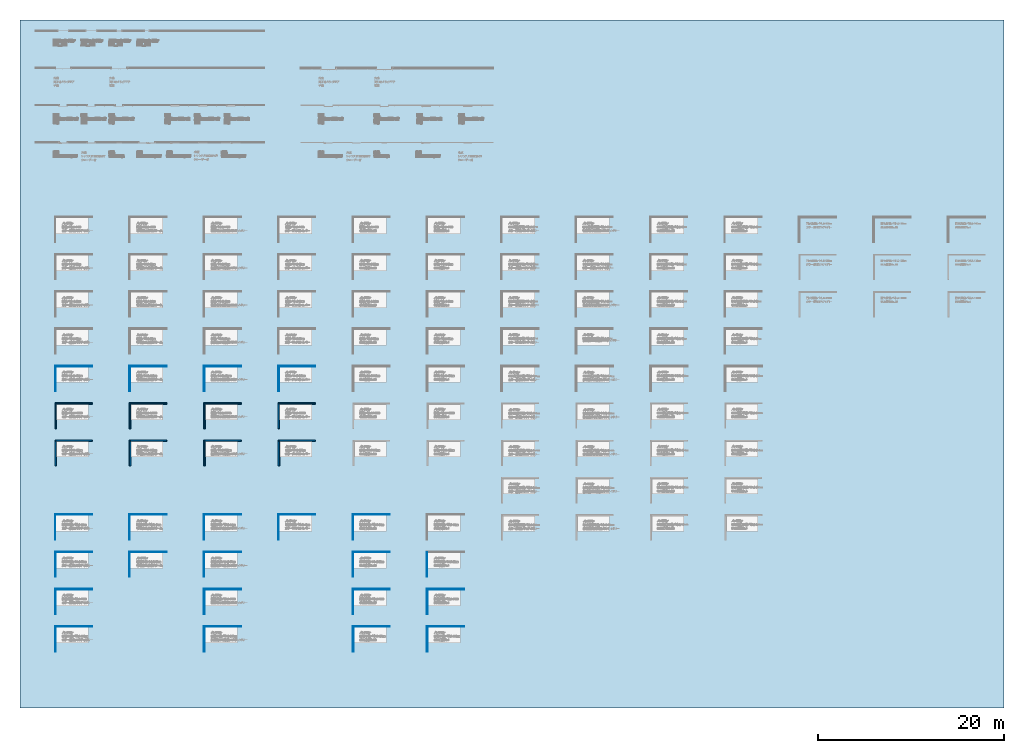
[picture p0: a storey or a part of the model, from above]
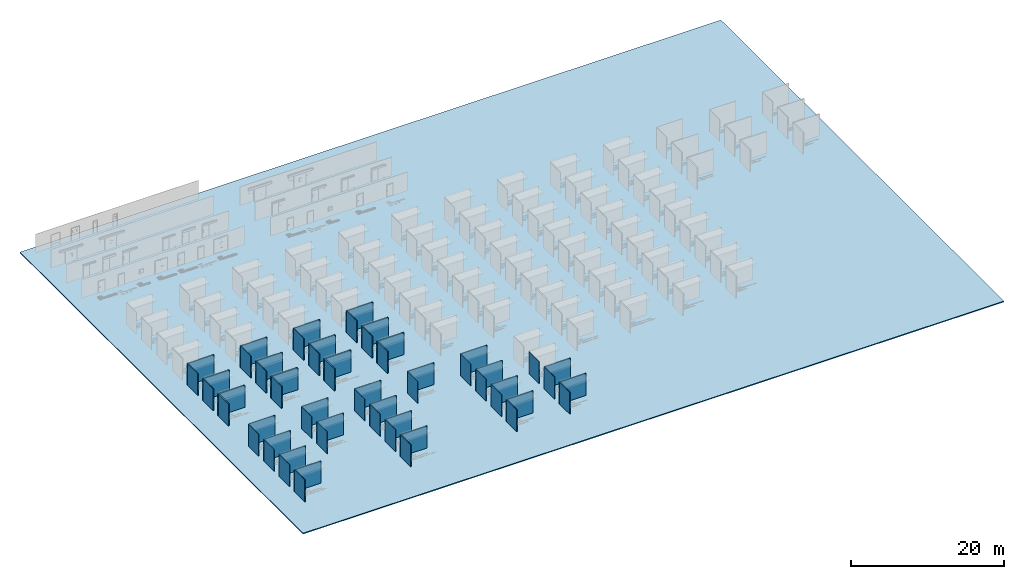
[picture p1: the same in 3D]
Properties of the parts of a building model (IFC2X3)

# File
Description: ViewDefinition [CoordinationView_V2.0], RevitIdentifiers [VersionGUID: c6d43900-80c5-4006-b426-6beda343c6e3, NumberOfSaves: 112], CoordinateReference [CoordinateBase: 共有座標]
File name: プロジェクト番号
Time: 2023-09-21T10:30:06
Written by: ODA IFC SDK 22.8
Made in: 22.1.40.58 - Exporter 22.6.2.0 - 代替 UI 22.6.2.0

# IfcProject, プロジェクト番号
LongName: プロジェクト名; Phase: プロジェクト ステータス

# IfcSite, Default
RefLatitude: 35, 41, 6, 4943; RefLongitude: 139, 45, 3, 625488; RefElevation: 0 mm

# IfcBuilding
Pset_BuildingCommon - NumberOfStoreys: 1

# IfcBuildingStorey: レベル:レベル記号 (2)
Name | LongName | Elevation (mm)
レベル 1 | レベル 1 | 500
レベル 2 | レベル 2 | 3500

# IfcBuildingStorey: レベル:レベル記号 - 基準, 設計GL
LongName: 設計GL; Elevation: 0 mm

# IfcBuildingElementProxy: 立体文字:200㎜ MS Pゴシック (136)
In: レベル 1
Pset_BuildingElementProxyCommon - Reference: 200㎜ MS Pゴシック; sets with these values: 2
Pset_ProvisionForVoid - Shape: Undefined
Name (立体文字:200㎜ MS Pゴシック:...) | Width (mm) | Height (mm) = Depth (mm)
365015 | 239.087 | 18.3913
365466 | 256.329 | 25.2881
365474 | 239.087 | 18.3913
365482 | 239.087 | 18.3913
365548 | 25.2881 | 158.625
365597 | 25.2881 | 158.625
365607 | 12.644 | 293.112
365695 | 66.6686 | 13.7935
365733 | 12.644 | 293.112
365739 | 12.644 | 293.112
365747 | 12.644 | 293.112
365796 | 25.2881 | 158.625
365804 | 66.6686 | 13.7935
365825 | 239.087 | 18.3913
365826 | 256.329 | 25.2881
365827 | 239.087 | 18.3913
365829 | 25.2881 | 158.625
365830 | 25.2881 | 158.625
365831 | 66.6686 | 13.7935
365833 | 66.6686 | 13.7935
365937 | 256.329 | 25.2881
365998 | 256.329 | 25.2881
366008 | 256.329 | 25.2881
366018 | 256.329 | 25.2881
366026 | 256.329 | 25.2881
366036 | 256.329 | 25.2881
366044 | 256.329 | 25.2881
366052 | 256.329 | 25.2881
366131 | 256.329 | 25.2881
366139 | 256.329 | 25.2881
366147 | 256.329 | 25.2881
366174 | 66.6686 | 13.7935
366219 | 66.6686 | 13.7935
366229 | 66.6686 | 13.7935
366237 | 66.6686 | 13.7935
366245 | 66.6686 | 13.7935
366253 | 66.6686 | 13.7935
366261 | 256.329 | 25.2881
366271 | 66.6686 | 13.7935
366324 | 66.6686 | 13.7935
366393 | 256.329 | 25.2881
366402 | 256.329 | 25.2881
366411
366422
366503 | 256.329 | 25.2881
366504 | 256.329 | 25.2881
366505
366506
366538 | 256.329 | 25.2881
366539 | 256.329 | 25.2881
366540
366541
366549 | 256.329 | 25.2881
366550 | 256.329 | 25.2881
366551
366552
366560 | 256.329 | 25.2881
366561 | 256.329 | 25.2881
366562
366563
366571 | 256.329 | 25.2881
366572 | 256.329 | 25.2881
366573
366574
366582 | 256.329 | 25.2881
366583 | 256.329 | 25.2881
366584
366585
366593 | 256.329 | 25.2881
366594 | 256.329 | 25.2881
366595
366596
366640 | 256.329 | 25.2881
366642
366643
366651 | 256.329 | 25.2881
366653
366654
366664 | 256.329 | 25.2881
366666
366667
453311 | 256.329 | 25.2881
453312 | 256.329 | 25.2881
453313 | 256.329 | 25.2881
453314 | 256.329 | 25.2881
453370 | 256.329 | 25.2881
453371 | 256.329 | 25.2881
453372 | 256.329 | 25.2881
453373 | 256.329 | 25.2881
453418 | 256.329 | 25.2881
453479 | 163.223 | 21.8397
457776 | 239.087 | 18.3913
461452 | 256.329 | 25.2881
465981 | 239.087 | 18.3913
470227 | 239.087 | 18.3913
473891 | 256.329 | 25.2881
520192 | 25.2881 | 158.625
524008 | 25.2881 | 158.625
535722 | 66.6686 | 13.7935
551148 | 25.2881 | 158.625
555094 | 66.6686 | 13.7935
720312 | 256.329 | 25.2881
720313 | 256.329 | 25.2881
720314 | 256.329 | 25.2881
720315 | 256.329 | 25.2881
720352 | 256.329 | 25.2881
720353 | 256.329 | 25.2881
720354 | 256.329 | 25.2881
720355 | 256.329 | 25.2881
720365 | 256.329 | 25.2881
720410 | 25.2881 | 26.4375
720506 | 25.2881 | 26.4375
720608 | 163.223 | 21.8397
720616 | 163.223 | 21.8397
720701 | 25.2881 | 26.4375
721289 | 25.2881 | 26.4375
721290 | 25.2881 | 26.4375
721298 | 25.2881 | 26.4375
721299 | 25.2881 | 26.4375
721307 | 25.2881 | 26.4375
721308 | 25.2881 | 26.4375
721316 | 25.2881 | 26.4375
721317 | 25.2881 | 26.4375
721327 | 25.2881 | 26.4375
721328 | 25.2881 | 26.4375
721336 | 25.2881 | 26.4375
721337 | 25.2881 | 26.4375
721345 | 25.2881 | 26.4375
721346 | 25.2881 | 26.4375
721354 | 25.2881 | 26.4375
721355 | 25.2881 | 26.4375
721387 | 25.2881 | 26.4375
722106 | 25.2881 | 26.4375
722107 | 25.2881 | 26.4375
722115 | 25.2881 | 26.4375
722116 | 25.2881 | 26.4375

# IfcCovering: 天井:g-p_ECO不燃断熱パネルt102+天井下地材t125_900x2700 (4)
In: レベル 1
Type - PredefinedType: CEILING
Type - Pset_CoveringCommon - TotalThickness: 227 mm
Material: <Unnamed> 125 mm, g-p_フェノールフォーム 102 mm
Pset_CoveringCommon - Reference: g-p_ECO不燃断熱パネルt102+天井下地材t125_900x2700; Finish: g-p_フェノールフォーム;
Pset_QuantityTakeOff - Reference: g-p_ECO不燃断熱パネルt102+天井下地材t125_900x2700
Name (天井:g-p_ECO不燃断熱パネルt102+天井下地材t125_900x2700:...)
453344
720326
720424
720520

# IfcCovering: 天井:g-p_ECO不燃断熱パネルt118+天井下地材t125_900x2700 (4)
In: レベル 1
Type - PredefinedType: CEILING
Type - Pset_CoveringCommon - TotalThickness: 243 mm
Material: <Unnamed> 125 mm, g-p_フェノールフォーム 118 mm
Pset_CoveringCommon - Reference: g-p_ECO不燃断熱パネルt118+天井下地材t125_900x2700; Finish: g-p_フェノールフォーム;
Pset_QuantityTakeOff - Reference: g-p_ECO不燃断熱パネルt118+天井下地材t125_900x2700
Name (天井:g-p_ECO不燃断熱パネルt118+天井下地材t125_900x2700:...)
453351
720333
720431
720527

# IfcCovering: 天井:g-p_ECO不燃断熱パネルt134+天井下地材t125_900x2700 (4)
In: レベル 1
Type - PredefinedType: CEILING
Type - Pset_CoveringCommon - TotalThickness: 259 mm
Material: <Unnamed> 125 mm, g-p_フェノールフォーム 134 mm
Pset_CoveringCommon - Reference: g-p_ECO不燃断熱パネルt134+天井下地材t125_900x2700; Finish: g-p_フェノールフォーム;
Pset_QuantityTakeOff - Reference: g-p_ECO不燃断熱パネルt134+天井下地材t125_900x2700
Name (天井:g-p_ECO不燃断熱パネルt134+天井下地材t125_900x2700:...)
453358
720340
720438
720534

# IfcCovering: 天井:g-p_ECO不燃断熱パネルt152+天井下地材t125_900x2700 (4)
In: レベル 1
Type - PredefinedType: CEILING
Type - Pset_CoveringCommon - TotalThickness: 277 mm
Material: <Unnamed> 125 mm, g-p_フェノールフォーム 152 mm
Pset_CoveringCommon - Reference: g-p_ECO不燃断熱パネルt152+天井下地材t125_900x2700; Finish: g-p_フェノールフォーム;
Pset_QuantityTakeOff - Reference: g-p_ECO不燃断熱パネルt152+天井下地材t125_900x2700
Name (天井:g-p_ECO不燃断熱パネルt152+天井下地材t125_900x2700:...)
453365
720347
720445
720541

# IfcCovering: 天井:g-p_ECO不燃断熱パネルt168+天井下地材t125_900x2700 (4)
In: レベル 1
Type - PredefinedType: CEILING
Type - Pset_CoveringCommon - TotalThickness: 293 mm
Material: <Unnamed> 125 mm, g-p_フェノールフォーム 168 mm
Pset_CoveringCommon - Reference: g-p_ECO不燃断熱パネルt168+天井下地材t125_900x2700; Finish: g-p_フェノールフォーム;
Pset_QuantityTakeOff - Reference: g-p_ECO不燃断熱パネルt168+天井下地材t125_900x2700
Name (天井:g-p_ECO不燃断熱パネルt168+天井下地材t125_900x2700:...)
453413
720360
720458
720554

# IfcCovering: 天井:g-p_ECO不燃断熱パネルt52+天井下地材t125_900x2700 (8)
In: レベル 1
Type - PredefinedType: CEILING
Type - Pset_CoveringCommon - TotalThickness: 177 mm
Material: <Unnamed> 125 mm, g-p_フェノールフォーム 52 mm
Pset_CoveringCommon - Reference: g-p_ECO不燃断熱パネルt52+天井下地材t125_900x2700; Finish: g-p_フェノールフォーム;
Pset_QuantityTakeOff - Reference: g-p_ECO不燃断熱パネルt52+天井下地材t125_900x2700
Name (天井:g-p_ECO不燃断熱パネルt52+天井下地材t125_900x2700:...)
453292
719525
720293
720368
720391
720466
720487
720562

# IfcCovering: 天井:g-p_ECO不燃断熱パネルt68+天井下地材t125_900x2700 (4)
In: レベル 1
Type - PredefinedType: CEILING
Type - Pset_CoveringCommon - TotalThickness: 193 mm
Material: <Unnamed> 125 mm, g-p_フェノールフォーム 68 mm
Pset_CoveringCommon - Reference: g-p_ECO不燃断熱パネルt68+天井下地材t125_900x2700; Finish: g-p_フェノールフォーム;
Pset_QuantityTakeOff - Reference: g-p_ECO不燃断熱パネルt68+天井下地材t125_900x2700
Name (天井:g-p_ECO不燃断熱パネルt68+天井下地材t125_900x2700:...)
453299
720300
720398
720494

# IfcCovering: 天井:g-p_ECO不燃断熱パネルt87+天井下地材t125_900x2700 (4)
In: レベル 1
Type - PredefinedType: CEILING
Type - Pset_CoveringCommon - TotalThickness: 212 mm
Material: <Unnamed> 125 mm, g-p_フェノールフォーム 87 mm
Pset_CoveringCommon - Reference: g-p_ECO不燃断熱パネルt87+天井下地材t125_900x2700; Finish: g-p_フェノールフォーム;
Pset_QuantityTakeOff - Reference: g-p_ECO不燃断熱パネルt87+天井下地材t125_900x2700
Name (天井:g-p_ECO不燃断熱パネルt87+天井下地材t125_900x2700:...)
453306
720307
720405
720501

# IfcCovering: 天井:g-p_不燃断熱パネルt100+天井下地材t125_900x2700 (4)
In: レベル 1
Type - PredefinedType: CEILING
Type - Pset_CoveringCommon - TotalThickness: 225 mm
Material: <Unnamed> 125 mm, g-p_硬質イソシアヌレートフォーム 100 mm
Pset_CoveringCommon - Reference: g-p_不燃断熱パネルt100+天井下地材t125_900x2700; Finish: g-p_硬質イソシアヌレートフォーム;
Pset_QuantityTakeOff - Reference: g-p_不燃断熱パネルt100+天井下地材t125_900x2700
Name (天井:g-p_不燃断熱パネルt100+天井下地材t125_900x2700:...)
356772
357047
357259
357363

# IfcCovering: 天井:g-p_不燃断熱パネルt44+天井下地材t125_900x2700 (6)
In: レベル 1
Type - PredefinedType: CEILING
Type - Pset_CoveringCommon - TotalThickness: 169 mm
Material: <Unnamed> 125 mm, g-p_硬質イソシアヌレートフォーム 44 mm
Pset_CoveringCommon - Reference: g-p_不燃断熱パネルt44+天井下地材t125_900x2700; Finish: g-p_硬質イソシアヌレートフォーム;
Pset_QuantityTakeOff - Reference: g-p_不燃断熱パネルt44+天井下地材t125_900x2700
Name (天井:g-p_不燃断熱パネルt44+天井下地材t125_900x2700:...)
356722
356920
357026
357132
357238
357342

# IfcCovering: 天井:g-p_不燃断熱パネルt50+天井下地材t125_900x2700 (5)
In: レベル 1
Type - PredefinedType: CEILING
Type - Pset_CoveringCommon - TotalThickness: 175 mm
Material: <Unnamed> 125 mm, g-p_硬質イソシアヌレートフォーム 50 mm
Pset_CoveringCommon - Reference: g-p_不燃断熱パネルt50+天井下地材t125_900x2700; Finish: g-p_硬質イソシアヌレートフォーム;
Pset_QuantityTakeOff - Reference: g-p_不燃断熱パネルt50+天井下地材t125_900x2700
Name (天井:g-p_不燃断熱パネルt50+天井下地材t125_900x2700:...)
356740
356927
357033
357245
357349

# IfcCovering: 天井:g-p_不燃断熱パネルt77+天井下地材t125_900x2700 (4)
In: レベル 1
Type - PredefinedType: CEILING
Type - Pset_CoveringCommon - TotalThickness: 202 mm
Material: <Unnamed> 125 mm, g-p_硬質イソシアヌレートフォーム 77 mm
Pset_CoveringCommon - Reference: g-p_不燃断熱パネルt77+天井下地材t125_900x2700; Finish: g-p_硬質イソシアヌレートフォーム;
Pset_QuantityTakeOff - Reference: g-p_不燃断熱パネルt77+天井下地材t125_900x2700
Name (天井:g-p_不燃断熱パネルt77+天井下地材t125_900x2700:...)
356756
357040
357252
357356

# IfcCovering: 天井:g-p_断熱パネルt100+天井下地材t125_900x2700 (6)
In: レベル 1
Type - PredefinedType: CEILING
Type - Pset_CoveringCommon - TotalThickness: 225 mm
Material: <Unnamed> 125 mm, g-p_硬質ウレタンフォーム 100 mm
Pset_CoveringCommon - Reference: g-p_断熱パネルt100+天井下地材t125_900x2700; Finish: g-p_硬質ウレタンフォーム;
Pset_QuantityTakeOff - Reference: g-p_断熱パネルt100+天井下地材t125_900x2700
Name (天井:g-p_断熱パネルt100+天井下地材t125_900x2700:...)
356674
356899
357005
357111
357217
357321

# IfcCovering: 天井:g-p_断熱パネルt127+天井下地材t125_900x2700 (6)
In: レベル 1
Type - PredefinedType: CEILING
Type - Pset_CoveringCommon - TotalThickness: 252 mm
Material: <Unnamed> 125 mm, g-p_硬質ウレタンフォーム 127 mm
Pset_CoveringCommon - Reference: g-p_断熱パネルt127+天井下地材t125_900x2700; Finish: g-p_硬質ウレタンフォーム;
Pset_QuantityTakeOff - Reference: g-p_断熱パネルt127+天井下地材t125_900x2700
Name (天井:g-p_断熱パネルt127+天井下地材t125_900x2700:...)
356690
356906
357012
357118
357224
357328

# IfcCovering: 天井:g-p_断熱パネルt152+天井下地材t125_900x2700 (6)
In: レベル 1
Type - PredefinedType: CEILING
Type - Pset_CoveringCommon - TotalThickness: 277 mm
Material: <Unnamed> 125 mm, g-p_硬質ウレタンフォーム 152 mm
Pset_CoveringCommon - Reference: g-p_断熱パネルt152+天井下地材t125_900x2700; Finish: g-p_硬質ウレタンフォーム;
Pset_QuantityTakeOff - Reference: g-p_断熱パネルt152+天井下地材t125_900x2700
Name (天井:g-p_断熱パネルt152+天井下地材t125_900x2700:...)
356706
356913
357019
357125
357231
357335

# IfcCovering: 天井:g-p_断熱パネルt44+天井下地材t125_900x2700 (6)
In: レベル 1
Type - PredefinedType: CEILING
Type - Pset_CoveringCommon - TotalThickness: 169 mm
Material: <Unnamed> 125 mm, g-p_硬質ウレタンフォーム 44 mm
Pset_CoveringCommon - Reference: g-p_断熱パネルt44+天井下地材t125_900x2700; Finish: g-p_硬質ウレタンフォーム;
Pset_QuantityTakeOff - Reference: g-p_断熱パネルt44+天井下地材t125_900x2700
Name (天井:g-p_断熱パネルt44+天井下地材t125_900x2700:...)
282149
356849
356955
357061
357167
357271

# IfcCovering: 天井:g-p_断熱パネルt50+天井下地材t125_900x2700 (6)
In: レベル 1
Type - PredefinedType: CEILING
Type - Pset_CoveringCommon - TotalThickness: 175 mm
Material: <Unnamed> 125 mm, g-p_硬質ウレタンフォーム 50 mm
Pset_CoveringCommon - Reference: g-p_断熱パネルt50+天井下地材t125_900x2700; Finish: g-p_硬質ウレタンフォーム;
Pset_QuantityTakeOff - Reference: g-p_断熱パネルt50+天井下地材t125_900x2700
Name (天井:g-p_断熱パネルt50+天井下地材t125_900x2700:...)
356626
356878
356984
357090
357196
357300

# IfcCovering: 天井:g-p_断熱パネルt62+天井下地材t125_900x2700 (6)
In: レベル 1
Type - PredefinedType: CEILING
Type - Pset_CoveringCommon - TotalThickness: 187 mm
Material: <Unnamed> 125 mm, g-p_硬質ウレタンフォーム 62 mm
Pset_CoveringCommon - Reference: g-p_断熱パネルt62+天井下地材t125_900x2700; Finish: g-p_硬質ウレタンフォーム;
Pset_QuantityTakeOff - Reference: g-p_断熱パネルt62+天井下地材t125_900x2700
Name (天井:g-p_断熱パネルt62+天井下地材t125_900x2700:...)
356642
356885
356991
357097
357203
357307

# IfcCovering: 天井:g-p_断熱パネルt77+天井下地材t125_900x2700 (6)
In: レベル 1
Type - PredefinedType: CEILING
Type - Pset_CoveringCommon - TotalThickness: 202 mm
Material: <Unnamed> 125 mm, g-p_硬質ウレタンフォーム 77 mm
Pset_CoveringCommon - Reference: g-p_断熱パネルt77+天井下地材t125_900x2700; Finish: g-p_硬質ウレタンフォーム;
Pset_QuantityTakeOff - Reference: g-p_断熱パネルt77+天井下地材t125_900x2700
Name (天井:g-p_断熱パネルt77+天井下地材t125_900x2700:...)
356658
356892
356998
357104
357210
357314

# IfcDoor: 両開きスイングドア_窓付_FCG:W1215xH2005xt40, 両開きスイングドア_窓付_FCG:W1215xH2005xt40:359119
In: レベル 1
Type - OperationType: DOUBLE_DOOR_DOUBLE_SWING; ParameterTakesPrecedence: no; Sizeable: no; Material: g-p_ゴム, g-p_樹脂, g-p_アクリル, g-p_アルミ, g-p_S_SUS鋼板No2B, g-p_SUS
Type - 両開きスイングドア_窓付_FCG:W1215xH2005xt40:359119:1 - PanelOperation: DOUBLE_ACTING
Type - Pset_DoorCommon - IsExternal: no
Type - Pset_ManufacturerTypeInformation - Manufacturer: ガリレイパネルクリエイト株式会社
OverallHeight: 2011 mm; OverallWidth: 1227 mm
Pset_DoorCommon - Reference: W1215xH2005xt40
Pset_QuantityTakeOff - Reference: W1215xH2005xt40

# IfcDoor: 両開きスイングドア_窓付_SCG:W1215xH2005xt21, 両開きスイングドア_窓付_SCG:W1215xH2005xt21:359231
In: レベル 1
Type - OperationType: DOUBLE_DOOR_DOUBLE_SWING; ParameterTakesPrecedence: no; Sizeable: no; Material: g-p_ゴム, g-p_樹脂, g-p_アクリル, g-p_アルミ, g-p_S_SUS鋼板No2B, g-p_SUS
Type - 両開きスイングドア_窓付_SCG:W1215xH2005xt21:359231:1 - PanelOperation: DOUBLE_ACTING
Type - Pset_DoorCommon - IsExternal: no
Type - Pset_ManufacturerTypeInformation - Manufacturer: ガリレイパネルクリエイト株式会社
OverallHeight: 2011 mm; OverallWidth: 1227 mm
Pset_DoorCommon - Reference: W1215xH2005xt21
Pset_QuantityTakeOff - Reference: W1215xH2005xt21

# IfcDoor: 冷凍_シリウス小扉:W500xH500xt100, 冷凍_シリウス小扉:W500xH500xt100:936785
In: レベル 1
Type - OperationType: DOUBLE_SWING_LEFT; ParameterTakesPrecedence: no; Sizeable: no; Material: g-p_樹脂, g-p_アルミ, g-p_S_カラー鋼板ソフトアイボリー, g-p_SUS, g-p_ゴム
Type - 冷凍_シリウス小扉:W500xH500xt100:936785:1 - PanelOperation: DOUBLE_ACTING
Type - Pset_DoorCommon - IsExternal: no
Type - Pset_ManufacturerTypeInformation - Manufacturer: ガリレイパネルクリエイト株式会社
OverallHeight: 532.001 mm; OverallWidth: 532.002 mm
Pset_DoorCommon - Reference: W500xH500xt100
Pset_QuantityTakeOff - Reference: W500xH500xt100

# IfcDoor: 冷凍_シリウス片開き扉3方:W870xH1855xt100, 冷凍_シリウス片開き扉3方:W870xH1855xt100:941146
In: レベル 1
Type - OperationType: DOUBLE_SWING_LEFT; ParameterTakesPrecedence: no; Sizeable: no; Material: g-p_樹脂, g-p_アルミ, g-p_S_カラー鋼板ソフトアイボリー, g-p_SUS, g-p_ゴム
Type - 冷凍_シリウス片開き扉3方:W870xH1855xt100:941146:1 - PanelOperation: DOUBLE_ACTING
Type - Pset_DoorCommon - IsExternal: no
Type - Pset_ManufacturerTypeInformation - Manufacturer: ガリレイパネルクリエイト株式会社
OverallHeight: 1871 mm; OverallWidth: 902.002 mm
Pset_DoorCommon - Reference: W870xH1855xt100
Pset_QuantityTakeOff - Reference: W870xH1855xt100

# IfcDoor: 冷凍_シリウス片開き扉3方_クローザー付:W870xH1855xt100, 冷凍_シリウス片開き扉3方_クローザー付:W870xH1855xt100:944777
In: レベル 1
Type - OperationType: DOUBLE_SWING_LEFT; ParameterTakesPrecedence: no; Sizeable: no; Material: g-p_鉄（亜鉛メッキ）, g-p_アルミ, g-p_樹脂, g-p_S_カラー鋼板ソフトアイボリー, g-p_ゴム
Type - 冷凍_シリウス片開き扉3方_クローザー付:W870xH1855xt100:944777:1 - PanelOperation: DOUBLE_ACTING
Type - Pset_DoorCommon - IsExternal: no
Type - Pset_ManufacturerTypeInformation - Manufacturer: ガリレイパネルクリエイト株式会社
OverallHeight: 1871 mm; OverallWidth: 902.002 mm
Pset_DoorCommon - Reference: W870xH1855xt100
Pset_QuantityTakeOff - Reference: W870xH1855xt100

# IfcDoor: 冷凍_シリウス片開き扉4方:W870xH1800xt100, 冷凍_シリウス片開き扉4方:W870xH1800xt100:660459
In: レベル 1
Type - OperationType: DOUBLE_SWING_LEFT; ParameterTakesPrecedence: no; Sizeable: no; Material: g-p_樹脂, g-p_アルミ, g-p_S_カラー鋼板ソフトアイボリー, g-p_SUS, g-p_ゴム
Type - 冷凍_シリウス片開き扉4方:W870xH1800xt100:660459:1 - PanelOperation: DOUBLE_ACTING
Type - Pset_DoorCommon - IsExternal: no
Type - Pset_ManufacturerTypeInformation - Manufacturer: ガリレイパネルクリエイト株式会社
OverallHeight: 1832 mm; OverallWidth: 902.002 mm
Pset_DoorCommon - Reference: W870xH1800xt100
Pset_QuantityTakeOff - Reference: W870xH1800xt100

# IfcDoor: 冷凍_シリウス片開き扉4方_クローザー付:W870xH1800xt100, 冷凍_シリウス片開き扉4方_クローザー付:W870xH1800xt100:473805
In: レベル 1
Type - OperationType: DOUBLE_SWING_LEFT; ParameterTakesPrecedence: no; Sizeable: no; Material: g-p_鉄（亜鉛メッキ）, g-p_アルミ, g-p_樹脂, g-p_S_カラー鋼板ソフトアイボリー, g-p_ゴム
Type - 冷凍_シリウス片開き扉4方_クローザー付:W870xH1800xt100:473805:1 - PanelOperation: DOUBLE_ACTING
Type - Pset_DoorCommon - IsExternal: no
Type - Pset_ManufacturerTypeInformation - Manufacturer: ガリレイパネルクリエイト株式会社
OverallHeight: 1832 mm; OverallWidth: 902.002 mm
Pset_DoorCommon - Reference: W870xH1800xt100
Pset_QuantityTakeOff - Reference: W870xH1800xt100

# IfcDoor: 冷凍_両引きスライドドア_手動:W1671xH2000xt100, 冷凍_両引きスライドドア_手動:W1671xH2000xt100:911284
In: レベル 1
Type - ParameterTakesPrecedence: no; Sizeable: no; Material: g-p_S_カラー鋼板ソフトアイボリー, g-p_樹脂, g-p_ゴム, g-p_SUS, g-p_アルミ
Type - Pset_DoorCommon - IsExternal: no
Type - Pset_ManufacturerTypeInformation - Manufacturer: ガリレイパネルクリエイト株式会社
OverallHeight: 2016 mm; OverallWidth: 1703 mm
Pset_DoorCommon - Reference: W1671xH2000xt100
Pset_QuantityTakeOff - Reference: W1671xH2000xt100

# IfcDoor: 冷凍_両引きスライドドア_電動:W1671xH2000xt100, 冷凍_両引きスライドドア_電動:W1671xH2000xt100:915086
In: レベル 1
Type - ParameterTakesPrecedence: no; Sizeable: no; Material: g-p_S_カラー鋼板ソフトアイボリー, g-p_樹脂, g-p_ゴム, g-p_SUS, g-p_アルミ
Type - Pset_DoorCommon - IsExternal: no
Type - Pset_ManufacturerTypeInformation - Manufacturer: ガリレイパネルクリエイト株式会社
OverallHeight: 2016 mm; OverallWidth: 1703 mm
Pset_DoorCommon - Reference: W1671xH2000xt100
Pset_QuantityTakeOff - Reference: W1671xH2000xt100

# IfcDoor: 冷凍_片引きスライドドア3方_手動:W870xH1905xt100, 冷凍_片引きスライドドア3方_手動:W870xH1905xt100:903880
In: レベル 1
Type - ParameterTakesPrecedence: no; Sizeable: no; Material: g-p_S_カラー鋼板ソフトアイボリー, g-p_樹脂, g-p_SUS, g-p_ゴム, g-p_アルミ
Type - Pset_DoorCommon - IsExternal: no
Type - Pset_ManufacturerTypeInformation - Manufacturer: ガリレイパネルクリエイト株式会社
OverallHeight: 1921 mm; OverallWidth: 902.002 mm
Pset_DoorCommon - Reference: W870xH1905xt100
Pset_QuantityTakeOff - Reference: W870xH1905xt100

# IfcDoor: 冷凍_片引きスライドドア3方_電動:W870xH1905xt100, 冷凍_片引きスライドドア3方_電動:W870xH1905xt100:907551
In: レベル 1
Type - ParameterTakesPrecedence: no; Sizeable: no; Material: g-p_S_カラー鋼板ソフトアイボリー, g-p_樹脂, g-p_SUS, g-p_ゴム, g-p_アルミ
Type - Pset_DoorCommon - IsExternal: no
Type - Pset_ManufacturerTypeInformation - Manufacturer: ガリレイパネルクリエイト株式会社
OverallHeight: 1921 mm; OverallWidth: 902.002 mm
Pset_DoorCommon - Reference: W870xH1905xt100
Pset_QuantityTakeOff - Reference: W870xH1905xt100

# IfcDoor: 冷凍_片引きスライドドア4方_手動:W870xH1800xt100, 冷凍_片引きスライドドア4方_手動:W870xH1800xt100:551156
In: レベル 1
Type - ParameterTakesPrecedence: no; Sizeable: no; Material: g-p_S_カラー鋼板ソフトアイボリー, g-p_樹脂, g-p_SUS, g-p_ゴム, g-p_アルミ
Type - Pset_DoorCommon - IsExternal: no
Type - Pset_ManufacturerTypeInformation - Manufacturer: ガリレイパネルクリエイト株式会社
OverallHeight: 1832 mm; OverallWidth: 902.002 mm
Pset_DoorCommon - Reference: W870xH1800xt100
Pset_QuantityTakeOff - Reference: W870xH1800xt100

# IfcDoor: 冷凍_片引きスライドドア4方_電動:W870xH1800xt100, 冷凍_片引きスライドドア4方_電動:W870xH1800xt100:535656
In: レベル 1
Type - ParameterTakesPrecedence: no; Sizeable: no; Material: g-p_S_カラー鋼板ソフトアイボリー, g-p_樹脂, g-p_SUS, g-p_ゴム, g-p_アルミ
Type - Pset_DoorCommon - IsExternal: no
Type - Pset_ManufacturerTypeInformation - Manufacturer: ガリレイパネルクリエイト株式会社
OverallHeight: 1832 mm; OverallWidth: 902.002 mm
Pset_DoorCommon - Reference: W870xH1800xt100
Pset_QuantityTakeOff - Reference: W870xH1800xt100

# IfcDoor: 冷蔵_シリウス両開き扉3方:W1770xH2055xt50, 冷蔵_シリウス両開き扉3方:W1770xH2055xt50:933141
In: レベル 1
Type - OperationType: DOUBLE_DOOR_DOUBLE_SWING; ParameterTakesPrecedence: no; Sizeable: no; Material: g-p_鉄（亜鉛メッキ）, g-p_アルミ, g-p_樹脂, g-p_S_カラー鋼板ソフトアイボリー, g-p_SUS, g-p_ゴム
Type - 冷蔵_シリウス両開き扉3方:W1770xH2055xt50:933141:1 - PanelOperation: DOUBLE_ACTING
Type - Pset_DoorCommon - IsExternal: no
Type - Pset_ManufacturerTypeInformation - Manufacturer: ガリレイパネルクリエイト株式会社
OverallHeight: 2071 mm; OverallWidth: 1802 mm
Pset_DoorCommon - Reference: W1770xH2055xt50
Pset_QuantityTakeOff - Reference: W1770xH2055xt50

# IfcDoor: 冷蔵_シリウス両開き扉4方:W2000xH2200xt50, 冷蔵_シリウス両開き扉4方:W2000xH2200xt50:655774
In: レベル 1
Type - OperationType: DOUBLE_DOOR_DOUBLE_SWING; ParameterTakesPrecedence: no; Sizeable: no; Material: g-p_鉄（亜鉛メッキ）, g-p_樹脂, g-p_アルミ, g-p_S_カラー鋼板ソフトアイボリー, g-p_SUS, g-p_ゴム
Type - 冷蔵_シリウス両開き扉4方:W2000xH2200xt50:655774:1 - PanelOperation: DOUBLE_ACTING
Type - Pset_DoorCommon - IsExternal: no
Type - Pset_ManufacturerTypeInformation - Manufacturer: ガリレイパネルクリエイト株式会社
OverallHeight: 2232 mm; OverallWidth: 2032 mm
Pset_DoorCommon - Reference: W2000xH2200xt50
Pset_QuantityTakeOff - Reference: W2000xH2200xt50

# IfcDoor: 冷蔵_シリウス小扉:W500xH500xt50, 冷蔵_シリウス小扉:W500xH500xt50:918702
In: レベル 1
Type - OperationType: DOUBLE_SWING_LEFT; ParameterTakesPrecedence: no; Sizeable: no; Material: g-p_樹脂, g-p_アルミ, g-p_S_カラー鋼板ソフトアイボリー, g-p_SUS, g-p_ゴム
Type - 冷蔵_シリウス小扉:W500xH500xt50:918702:1 - PanelOperation: DOUBLE_ACTING
Type - Pset_DoorCommon - IsExternal: no
Type - Pset_ManufacturerTypeInformation - Manufacturer: ガリレイパネルクリエイト株式会社
OverallHeight: 532.001 mm; OverallWidth: 532.002 mm
Pset_DoorCommon - Reference: W500xH500xt50
Pset_QuantityTakeOff - Reference: W500xH500xt50

# IfcDoor: 冷蔵_シリウス片開き扉3方:W870xH1855xt50, 冷蔵_シリウス片開き扉3方:W870xH1855xt50:923062
In: レベル 1
Type - OperationType: DOUBLE_SWING_LEFT; ParameterTakesPrecedence: no; Sizeable: no; Material: g-p_樹脂, g-p_アルミ, g-p_S_カラー鋼板ソフトアイボリー, g-p_SUS, g-p_ゴム
Type - 冷蔵_シリウス片開き扉3方:W870xH1855xt50:923062:1 - PanelOperation: DOUBLE_ACTING
Type - Pset_DoorCommon - IsExternal: no
Type - Pset_ManufacturerTypeInformation - Manufacturer: ガリレイパネルクリエイト株式会社
OverallHeight: 1871 mm; OverallWidth: 902.002 mm
Pset_DoorCommon - Reference: W870xH1855xt50
Pset_QuantityTakeOff - Reference: W870xH1855xt50

# IfcDoor: 冷蔵_シリウス片開き扉3方_クローザー付:W870xH1855xt50, 冷蔵_シリウス片開き扉3方_クローザー付:W870xH1855xt50:926695
In: レベル 1
Type - OperationType: DOUBLE_SWING_LEFT; ParameterTakesPrecedence: no; Sizeable: no; Material: g-p_鉄（亜鉛メッキ）, g-p_アルミ, g-p_樹脂, g-p_S_カラー鋼板ソフトアイボリー, g-p_ゴム
Type - 冷蔵_シリウス片開き扉3方_クローザー付:W870xH1855xt50:926695:1 - PanelOperation: DOUBLE_ACTING
Type - Pset_DoorCommon - IsExternal: no
Type - Pset_ManufacturerTypeInformation - Manufacturer: ガリレイパネルクリエイト株式会社
OverallHeight: 1871 mm; OverallWidth: 902.002 mm
Pset_DoorCommon - Reference: W870xH1855xt50
Pset_QuantityTakeOff - Reference: W870xH1855xt50

# IfcDoor: 冷蔵_シリウス片開き扉4方:W870xH1800xt50, 冷蔵_シリウス片開き扉4方:W870xH1800xt50:728773
In: レベル 1
Type - OperationType: DOUBLE_SWING_LEFT; ParameterTakesPrecedence: no; Sizeable: no; Material: g-p_樹脂, g-p_アルミ, g-p_S_カラー鋼板ソフトアイボリー, g-p_SUS, g-p_ゴム
Type - 冷蔵_シリウス片開き扉4方:W870xH1800xt50:728773:1 - PanelOperation: DOUBLE_ACTING
Type - Pset_DoorCommon - IsExternal: no
Type - Pset_ManufacturerTypeInformation - Manufacturer: ガリレイパネルクリエイト株式会社
OverallHeight: 1832 mm; OverallWidth: 902.002 mm
Pset_DoorCommon - Reference: W870xH1800xt50
Pset_QuantityTakeOff - Reference: W870xH1800xt50

# IfcDoor: 冷蔵_シリウス片開き扉4方_クローザー付:W870xH1800xt50, 冷蔵_シリウス片開き扉4方_クローザー付:W870xH1800xt50:650930
In: レベル 1
Type - OperationType: DOUBLE_SWING_LEFT; ParameterTakesPrecedence: no; Sizeable: no; Material: g-p_鉄（亜鉛メッキ）, g-p_アルミ, g-p_樹脂, g-p_S_カラー鋼板ソフトアイボリー, g-p_ゴム
Type - 冷蔵_シリウス片開き扉4方_クローザー付:W870xH1800xt50:650930:1 - PanelOperation: DOUBLE_ACTING
Type - Pset_DoorCommon - IsExternal: no
Type - Pset_ManufacturerTypeInformation - Manufacturer: ガリレイパネルクリエイト株式会社
OverallHeight: 1832 mm; OverallWidth: 902.002 mm
Pset_DoorCommon - Reference: W870xH1800xt50
Pset_QuantityTakeOff - Reference: W870xH1800xt50

# IfcDoor: 冷蔵_両引きスライドドア_手動:W1671xH2000xt50, 冷蔵_両引きスライドドア_手動:W1671xH2000xt50:896353
In: レベル 1
Type - ParameterTakesPrecedence: no; Sizeable: no; Material: g-p_S_カラー鋼板ソフトアイボリー, g-p_樹脂, g-p_ゴム, g-p_SUS, g-p_アルミ
Type - Pset_DoorCommon - IsExternal: no
Type - Pset_ManufacturerTypeInformation - Manufacturer: ガリレイパネルクリエイト株式会社
OverallHeight: 2016 mm; OverallWidth: 1703 mm
Pset_DoorCommon - Reference: W1671xH2000xt50
Pset_QuantityTakeOff - Reference: W1671xH2000xt50

# IfcDoor: 冷蔵_両引きスライドドア_電動:W1671xH2000xt50, 冷蔵_両引きスライドドア_電動:W1671xH2000xt50:900208
In: レベル 1
Type - ParameterTakesPrecedence: no; Sizeable: no; Material: g-p_S_カラー鋼板ソフトアイボリー, g-p_樹脂, g-p_ゴム, g-p_SUS, g-p_アルミ
Type - Pset_DoorCommon - IsExternal: no
Type - Pset_ManufacturerTypeInformation - Manufacturer: ガリレイパネルクリエイト株式会社
OverallHeight: 2016 mm; OverallWidth: 1703 mm
Pset_DoorCommon - Reference: W1671xH2000xt50
Pset_QuantityTakeOff - Reference: W1671xH2000xt50

# IfcDoor: 冷蔵_片引きスライドドア3方_手動:W870xH1905xt55, 冷蔵_片引きスライドドア3方_手動:W870xH1905xt55:889056
In: レベル 1
Type - ParameterTakesPrecedence: no; Sizeable: no; Material: g-p_S_カラー鋼板ソフトアイボリー, g-p_樹脂, g-p_SUS, g-p_ゴム, g-p_アルミ
Type - Pset_DoorCommon - IsExternal: no
Type - Pset_ManufacturerTypeInformation - Manufacturer: ガリレイパネルクリエイト株式会社
OverallHeight: 1921 mm; OverallWidth: 902.002 mm
Pset_DoorCommon - Reference: W870xH1905xt55
Pset_QuantityTakeOff - Reference: W870xH1905xt55

# IfcDoor: 冷蔵_片引きスライドドア3方_自閉:W870xH1905xt55, 冷蔵_片引きスライドドア3方_自閉:W870xH1905xt55:885469
In: レベル 1
Type - ParameterTakesPrecedence: no; Sizeable: no; Material: g-p_S_カラー鋼板ソフトアイボリー, g-p_樹脂, g-p_SUS, g-p_ゴム, g-p_アルミ
Type - Pset_DoorCommon - IsExternal: no
Type - Pset_ManufacturerTypeInformation - Manufacturer: ガリレイパネルクリエイト株式会社
OverallHeight: 1921 mm; OverallWidth: 902.002 mm
Pset_DoorCommon - Reference: W870xH1905xt55
Pset_QuantityTakeOff - Reference: W870xH1905xt55

# IfcDoor: 冷蔵_片引きスライドドア3方_電動:W870xH1905xt55, 冷蔵_片引きスライドドア3方_電動:W870xH1905xt55:892681
In: レベル 1
Type - ParameterTakesPrecedence: no; Sizeable: no; Material: g-p_S_カラー鋼板ソフトアイボリー, g-p_樹脂, g-p_SUS, g-p_ゴム, g-p_アルミ
Type - Pset_DoorCommon - IsExternal: no
Type - Pset_ManufacturerTypeInformation - Manufacturer: ガリレイパネルクリエイト株式会社
OverallHeight: 1921 mm; OverallWidth: 902.002 mm
Pset_DoorCommon - Reference: W870xH1905xt55
Pset_QuantityTakeOff - Reference: W870xH1905xt55

# IfcDoor: 冷蔵_片引きスライドドア4方_手動:W870xH1800xt55, 冷蔵_片引きスライドドア4方_手動:W870xH1800xt55:523953
In: レベル 1
Type - ParameterTakesPrecedence: no; Sizeable: no; Material: g-p_S_カラー鋼板ソフトアイボリー, g-p_樹脂, g-p_SUS, g-p_ゴム, g-p_アルミ
Type - Pset_DoorCommon - IsExternal: no
Type - Pset_ManufacturerTypeInformation - Manufacturer: ガリレイパネルクリエイト株式会社
OverallHeight: 1832 mm; OverallWidth: 902.002 mm
Pset_DoorCommon - Reference: W870xH1800xt55
Pset_QuantityTakeOff - Reference: W870xH1800xt55

# IfcDoor: 冷蔵_片引きスライドドア4方_自閉:W870xH1800xt55, 冷蔵_片引きスライドドア4方_自閉:W870xH1800xt55:543265
In: レベル 1
Type - ParameterTakesPrecedence: no; Sizeable: no; Material: g-p_S_カラー鋼板ソフトアイボリー, g-p_樹脂, g-p_SUS, g-p_ゴム, g-p_アルミ
Type - Pset_DoorCommon - IsExternal: no
Type - Pset_ManufacturerTypeInformation - Manufacturer: ガリレイパネルクリエイト株式会社
OverallHeight: 1832 mm; OverallWidth: 902.002 mm
Pset_DoorCommon - Reference: W870xH1800xt55
Pset_QuantityTakeOff - Reference: W870xH1800xt55

# IfcDoor: 冷蔵_片引きスライドドア4方_電動:W870xH1800xt55, 冷蔵_片引きスライドドア4方_電動:W870xH1800xt55:558887
In: レベル 1
Type - ParameterTakesPrecedence: no; Sizeable: no; Material: g-p_S_カラー鋼板ソフトアイボリー, g-p_樹脂, g-p_SUS, g-p_ゴム, g-p_アルミ
Type - Pset_DoorCommon - IsExternal: no
Type - Pset_ManufacturerTypeInformation - Manufacturer: ガリレイパネルクリエイト株式会社
OverallHeight: 1832 mm; OverallWidth: 902.002 mm
Pset_DoorCommon - Reference: W870xH1800xt55
Pset_QuantityTakeOff - Reference: W870xH1800xt55

# IfcDoor: 片開きスイングドア_窓付_FCG:W610xH2005xt40, 片開きスイングドア_窓付_FCG:W610xH2005xt40:360280
In: レベル 1
Type - OperationType: DOUBLE_SWING_RIGHT; ParameterTakesPrecedence: no; Sizeable: no; Material: g-p_ゴム, g-p_樹脂, g-p_アクリル, g-p_アルミ, g-p_SUS, g-p_S_SUS鋼板No2B
Type - 片開きスイングドア_窓付_FCG:W610xH2005xt40:360280:1 - PanelOperation: DOUBLE_ACTING
Type - Pset_DoorCommon - IsExternal: no
Type - Pset_ManufacturerTypeInformation - Manufacturer: ガリレイパネルクリエイト株式会社
OverallHeight: 2011 mm; OverallWidth: 622.001 mm
Pset_DoorCommon - Reference: W610xH2005xt40
Pset_QuantityTakeOff - Reference: W610xH2005xt40

# IfcDoor: 片開きスイングドア_窓付_SCG:W610xH2005xt21, 片開きスイングドア_窓付_SCG:W610xH2005xt21:360391
In: レベル 1
Type - OperationType: DOUBLE_SWING_LEFT; ParameterTakesPrecedence: no; Sizeable: no; Material: g-p_ゴム, g-p_樹脂, g-p_アクリル, g-p_アルミ, g-p_SUS, g-p_S_SUS鋼板No2B
Type - 片開きスイングドア_窓付_SCG:W610xH2005xt21:360391:1 - PanelOperation: DOUBLE_ACTING
Type - Pset_DoorCommon - IsExternal: no
Type - Pset_ManufacturerTypeInformation - Manufacturer: ガリレイパネルクリエイト株式会社
OverallHeight: 2011 mm; OverallWidth: 622.001 mm
Pset_DoorCommon - Reference: W610xH2005xt21
Pset_QuantityTakeOff - Reference: W610xH2005xt21

# IfcSlab: 床:一般 150 mm, 床:一般 150 mm:666478
In: レベル 1
Type - PredefinedType: FLOOR; Material: <Unnamed> 150 mm
Type - Pset_SlabCommon - IsExternal: no
Pset_QuantityTakeOff - Reference: 一般 150 mm; sets with these values: 2
Pset_SlabCommon - LoadBearing: no; Reference: 一般 150 mm; PitchAngle: 0 deg

# IfcWallStandardCase: 標準壁:g-p_ECO不燃断熱パネル(フラット)t102 (8)
In: レベル 1
Type - PredefinedType: STANDARD; Material: g-p_フェノールフォーム 102 mm
Type - Pset_WallCommon - IsExternal: yes
Pset_QuantityTakeOff - Reference: g-p_ECO不燃断熱パネル(フラット)t102; sets with these values: 2
Pset_WallCommon - ExtendToStructure: no; LoadBearing: no; Reference: g-p_ECO不燃断熱パネル(フラット)t102
Name (標準壁:g-p_ECO不燃断熱パネル(フラット)t102:...)
453334
453335
720316
720317
720414
720415
720510
720511

# IfcWallStandardCase: 標準壁:g-p_ECO不燃断熱パネル(フラット)t118 (8)
In: レベル 1
Type - PredefinedType: STANDARD; Material: g-p_フェノールフォーム 118 mm
Type - Pset_WallCommon - IsExternal: yes
Pset_QuantityTakeOff - Reference: g-p_ECO不燃断熱パネル(フラット)t118; sets with these values: 2
Pset_WallCommon - ExtendToStructure: no; LoadBearing: no; Reference: g-p_ECO不燃断熱パネル(フラット)t118
Name (標準壁:g-p_ECO不燃断熱パネル(フラット)t118:...)
453336
453337
720318
720319
720416
720417
720512
720513

# IfcWallStandardCase: 標準壁:g-p_ECO不燃断熱パネル(フラット)t134 (8)
In: レベル 1
Type - PredefinedType: STANDARD; Material: g-p_フェノールフォーム 134 mm
Type - Pset_WallCommon - IsExternal: yes
Pset_QuantityTakeOff - Reference: g-p_ECO不燃断熱パネル(フラット)t134; sets with these values: 2
Pset_WallCommon - ExtendToStructure: no; LoadBearing: no; Reference: g-p_ECO不燃断熱パネル(フラット)t134
Name (標準壁:g-p_ECO不燃断熱パネル(フラット)t134:...)
453338
453339
720320
720321
720418
720419
720514
720515

# IfcWallStandardCase: 標準壁:g-p_ECO不燃断熱パネル(フラット)t152 (8)
In: レベル 1
Type - PredefinedType: STANDARD; Material: g-p_フェノールフォーム 152 mm
Type - Pset_WallCommon - IsExternal: yes
Pset_QuantityTakeOff - Reference: g-p_ECO不燃断熱パネル(フラット)t152; sets with these values: 2
Pset_WallCommon - ExtendToStructure: no; LoadBearing: no; Reference: g-p_ECO不燃断熱パネル(フラット)t152
Name (標準壁:g-p_ECO不燃断熱パネル(フラット)t152:...)
453340
453341
720322
720323
720420
720421
720516
720517

# IfcWallStandardCase: 標準壁:g-p_ECO不燃断熱パネル(フラット)t168 (8)
In: レベル 1
Type - PredefinedType: STANDARD; Material: g-p_フェノールフォーム 168 mm
Type - Pset_WallCommon - IsExternal: yes
Pset_QuantityTakeOff - Reference: g-p_ECO不燃断熱パネル(フラット)t168; sets with these values: 2
Pset_WallCommon - ExtendToStructure: no; LoadBearing: no; Reference: g-p_ECO不燃断熱パネル(フラット)t168
Name (標準壁:g-p_ECO不燃断熱パネル(フラット)t168:...)
453409
453410
720356
720357
720454
720455
720550
720551

# IfcWallStandardCase: 標準壁:g-p_ECO不燃断熱パネル(フラット)t37 (8)
In: レベル 1
Type - PredefinedType: STANDARD; Material: g-p_フェノールフォーム 37 mm
Type - Pset_WallCommon - IsExternal: yes
Pset_QuantityTakeOff - Reference: g-p_ECO不燃断熱パネル(フラット)t37; sets with these values: 2
Pset_WallCommon - ExtendToStructure: no; LoadBearing: no; Reference: g-p_ECO不燃断熱パネル(フラット)t37
Name (標準壁:g-p_ECO不燃断熱パネル(フラット)t37:...)
453275
453276
720283
720284
720381
720382
720477
720478

# IfcWallStandardCase: 標準壁:g-p_ECO不燃断熱パネル(フラット)t52 (8)
In: レベル 1
Type - PredefinedType: STANDARD; Material: g-p_フェノールフォーム 52 mm
Type - Pset_WallCommon - IsExternal: yes
Pset_QuantityTakeOff - Reference: g-p_ECO不燃断熱パネル(フラット)t52; sets with these values: 2
Pset_WallCommon - ExtendToStructure: no; LoadBearing: no; Reference: g-p_ECO不燃断熱パネル(フラット)t52
Name (標準壁:g-p_ECO不燃断熱パネル(フラット)t52:...)
453277
453278
720285
720286
720383
720384
720479
720480

# IfcWallStandardCase: 標準壁:g-p_ECO不燃断熱パネル(フラット)t68 (8)
In: レベル 1
Type - PredefinedType: STANDARD; Material: g-p_フェノールフォーム 68 mm
Type - Pset_WallCommon - IsExternal: yes
Pset_QuantityTakeOff - Reference: g-p_ECO不燃断熱パネル(フラット)t68; sets with these values: 2
Pset_WallCommon - ExtendToStructure: no; LoadBearing: no; Reference: g-p_ECO不燃断熱パネル(フラット)t68
Name (標準壁:g-p_ECO不燃断熱パネル(フラット)t68:...)
453279
453280
720287
720288
720385
720386
720481
720482

# IfcWallStandardCase: 標準壁:g-p_ECO不燃断熱パネル(フラット)t87 (8)
In: レベル 1
Type - PredefinedType: STANDARD; Material: g-p_フェノールフォーム 87 mm
Type - Pset_WallCommon - IsExternal: yes
Pset_QuantityTakeOff - Reference: g-p_ECO不燃断熱パネル(フラット)t87; sets with these values: 2
Pset_WallCommon - ExtendToStructure: no; LoadBearing: no; Reference: g-p_ECO不燃断熱パネル(フラット)t87
Name (標準壁:g-p_ECO不燃断熱パネル(フラット)t87:...)
453281
453282
720289
720290
720387
720388
720483
720484

# IfcWallStandardCase: 標準壁:g-p_不燃断熱パネル(フラット)t100 (11)
In: レベル 1
Type - PredefinedType: STANDARD; Material: g-p_硬質イソシアヌレートフォーム 100 mm
Type - Pset_WallCommon - IsExternal: yes
Pset_QuantityTakeOff - Reference: g-p_不燃断熱パネル(フラット)t100; sets with these values: 2
Pset_WallCommon - ExtendToStructure: no; LoadBearing: no; Reference: g-p_不燃断熱パネル(フラット)t100
Name (標準壁:g-p_不燃断熱パネル(フラット)t100:...)
355856
355857
356980
356981
357192
357193
357296
357297
357822
357894
357943

# IfcWallStandardCase: 標準壁:g-p_不燃断熱パネル(フラット)t44 (12)
In: レベル 1
Type - PredefinedType: STANDARD; Material: g-p_硬質イソシアヌレートフォーム 44 mm
Type - Pset_WallCommon - IsExternal: yes
Pset_QuantityTakeOff - Reference: g-p_不燃断熱パネル(フラット)t44; sets with these values: 2
Pset_WallCommon - ExtendToStructure: no; LoadBearing: no; Reference: g-p_不燃断熱パネル(フラット)t44
Name (標準壁:g-p_不燃断熱パネル(フラット)t44:...)
355850
355851
356868
356869
356974
356975
357080
357081
357186
357187
357290
357291

# IfcWallStandardCase: 標準壁:g-p_不燃断熱パネル(フラット)t50 (10)
In: レベル 1
Type - PredefinedType: STANDARD; Material: g-p_硬質イソシアヌレートフォーム 50 mm
Type - Pset_WallCommon - IsExternal: yes
Pset_QuantityTakeOff - Reference: g-p_不燃断熱パネル(フラット)t50; sets with these values: 2
Pset_WallCommon - ExtendToStructure: no; LoadBearing: no; Reference: g-p_不燃断熱パネル(フラット)t50
Name (標準壁:g-p_不燃断熱パネル(フラット)t50:...)
355852
355853
356870
356871
356976
356977
357188
357189
357292
357293

# IfcWallStandardCase: 標準壁:g-p_不燃断熱パネル(フラット)t77 (8)
In: レベル 1
Type - PredefinedType: STANDARD; Material: g-p_硬質イソシアヌレートフォーム 77 mm
Type - Pset_WallCommon - IsExternal: yes
Pset_QuantityTakeOff - Reference: g-p_不燃断熱パネル(フラット)t77; sets with these values: 2
Pset_WallCommon - ExtendToStructure: no; LoadBearing: no; Reference: g-p_不燃断熱パネル(フラット)t77
Name (標準壁:g-p_不燃断熱パネル(フラット)t77:...)
355854
355855
356978
356979
357190
357191
357294
357295

# IfcWallStandardCase: 標準壁:g-p_断熱パネル(フラット)t100 (12)
In: レベル 1
Type - PredefinedType: STANDARD; Material: g-p_硬質ウレタンフォーム 100 mm
Type - Pset_WallCommon - IsExternal: yes
Pset_QuantityTakeOff - Reference: g-p_断熱パネル(フラット)t100; sets with these values: 2
Pset_WallCommon - ExtendToStructure: no; LoadBearing: no; Reference: g-p_断熱パネル(フラット)t100
Name (標準壁:g-p_断熱パネル(フラット)t100:...)
355844
355845
356862
356863
356968
356969
357074
357075
357180
357181
357284
357285

# IfcWallStandardCase: 標準壁:g-p_断熱パネル(フラット)t127 (12)
In: レベル 1
Type - PredefinedType: STANDARD; Material: g-p_硬質ウレタンフォーム 127 mm
Type - Pset_WallCommon - IsExternal: yes
Pset_QuantityTakeOff - Reference: g-p_断熱パネル(フラット)t127; sets with these values: 2
Pset_WallCommon - ExtendToStructure: no; LoadBearing: no; Reference: g-p_断熱パネル(フラット)t127
Name (標準壁:g-p_断熱パネル(フラット)t127:...)
355846
355847
356864
356865
356970
356971
357076
357077
357182
357183
357286
357287

# IfcWallStandardCase: 標準壁:g-p_断熱パネル(フラット)t152 (12)
In: レベル 1
Type - PredefinedType: STANDARD; Material: g-p_硬質ウレタンフォーム 152 mm
Type - Pset_WallCommon - IsExternal: yes
Pset_QuantityTakeOff - Reference: g-p_断熱パネル(フラット)t152; sets with these values: 2
Pset_WallCommon - ExtendToStructure: no; LoadBearing: no; Reference: g-p_断熱パネル(フラット)t152
Name (標準壁:g-p_断熱パネル(フラット)t152:...)
355848
355849
356866
356867
356972
356973
357078
357079
357184
357185
357288
357289

# IfcWallStandardCase: 標準壁:g-p_断熱パネル(フラット)t44 (16)
In: レベル 1
Type - PredefinedType: STANDARD; Material: g-p_硬質ウレタンフォーム 44 mm
Type - Pset_WallCommon - IsExternal: yes
Pset_QuantityTakeOff - Reference: g-p_断熱パネル(フラット)t44; sets with these values: 2
Pset_WallCommon - Reference: g-p_断熱パネル(フラット)t44; ExtendToStructure: no; LoadBearing: no
Name (標準壁:g-p_断熱パネル(フラット)t44:...)
355836
355837
356854
356855
356960
356961
357066
357067
357172
357173
357276
357277
357455
357566
357651
357716

# IfcWallStandardCase: 標準壁:g-p_断熱パネル(フラット)t50 (12)
In: レベル 1
Type - PredefinedType: STANDARD; Material: g-p_硬質ウレタンフォーム 50 mm
Type - Pset_WallCommon - IsExternal: yes
Pset_QuantityTakeOff - Reference: g-p_断熱パネル(フラット)t50; sets with these values: 2
Pset_WallCommon - ExtendToStructure: no; LoadBearing: no; Reference: g-p_断熱パネル(フラット)t50
Name (標準壁:g-p_断熱パネル(フラット)t50:...)
355838
355839
356856
356857
356962
356963
357068
357069
357174
357175
357278
357279

# IfcWallStandardCase: 標準壁:g-p_断熱パネル(フラット)t62 (12)
In: レベル 1
Type - PredefinedType: STANDARD; Material: g-p_硬質ウレタンフォーム 62 mm
Type - Pset_WallCommon - IsExternal: yes
Pset_QuantityTakeOff - Reference: g-p_断熱パネル(フラット)t62; sets with these values: 2
Pset_WallCommon - ExtendToStructure: no; LoadBearing: no; Reference: g-p_断熱パネル(フラット)t62
Name (標準壁:g-p_断熱パネル(フラット)t62:...)
355840
355841
356858
356859
356964
356965
357070
357071
357176
357177
357280
357281

# IfcWallStandardCase: 標準壁:g-p_断熱パネル(フラット)t77 (12)
In: レベル 1
Type - PredefinedType: STANDARD; Material: g-p_硬質ウレタンフォーム 77 mm
Type - Pset_WallCommon - IsExternal: yes
Pset_QuantityTakeOff - Reference: g-p_断熱パネル(フラット)t77; sets with these values: 2
Pset_WallCommon - ExtendToStructure: no; LoadBearing: no; Reference: g-p_断熱パネル(フラット)t77
Name (標準壁:g-p_断熱パネル(フラット)t77:...)
355842
355843
356860
356861
356966
356967
357072
357073
357178
357179
357282
357283

# IfcWallStandardCase: 標準壁:g-p_耐火断熱パネル(フラット)t100 (6)
In: レベル 1
Type - PredefinedType: STANDARD; Material: g-p_ロックウール 100 mm
Type - Pset_WallCommon - IsExternal: yes
Pset_QuantityTakeOff - Reference: g-p_耐火断熱パネル(フラット)t100; sets with these values: 2
Pset_WallCommon - ExtendToStructure: no; LoadBearing: no; Reference: g-p_耐火断熱パネル(フラット)t100
Name (標準壁:g-p_耐火断熱パネル(フラット)t100:...)
453459
453460
720695
720696
721381
721382

# IfcWallStandardCase: 標準壁:g-p_耐火断熱パネル(フラット)t125 (6)
In: レベル 1
Type - PredefinedType: STANDARD; Material: g-p_ロックウール 125 mm
Type - Pset_WallCommon - IsExternal: yes
Pset_QuantityTakeOff - Reference: g-p_耐火断熱パネル(フラット)t125; sets with these values: 2
Pset_WallCommon - ExtendToStructure: no; LoadBearing: no; Reference: g-p_耐火断熱パネル(フラット)t125
Name (標準壁:g-p_耐火断熱パネル(フラット)t125:...)
453461
453462
720697
720698
721383
721384

# IfcWallStandardCase: 標準壁:g-p_耐火断熱パネル(フラット)t150 (6)
In: レベル 1
Type - PredefinedType: STANDARD; Material: g-p_ロックウール 150 mm
Type - Pset_WallCommon - IsExternal: yes
Pset_QuantityTakeOff - Reference: g-p_耐火断熱パネル(フラット)t150; sets with these values: 2
Pset_WallCommon - ExtendToStructure: no; LoadBearing: no; Reference: g-p_耐火断熱パネル(フラット)t150
Name (標準壁:g-p_耐火断熱パネル(フラット)t150:...)
453463
453464
720699
720700
721385
721386
